One B-rep face of a CAD part: STEP entity #277.
In plain terms, the cylindrical face has radius 42.5 mm (diameter 85 mm), a partial arc.
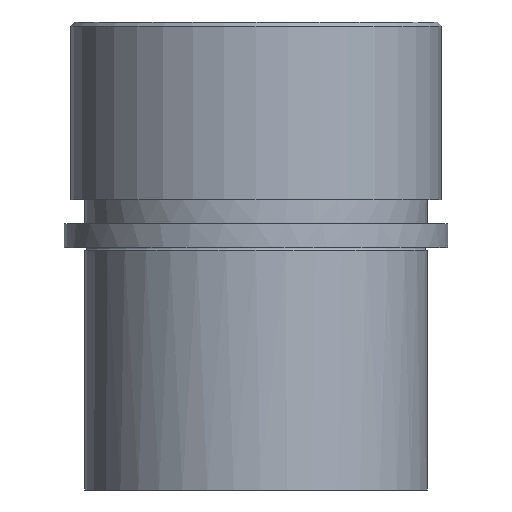
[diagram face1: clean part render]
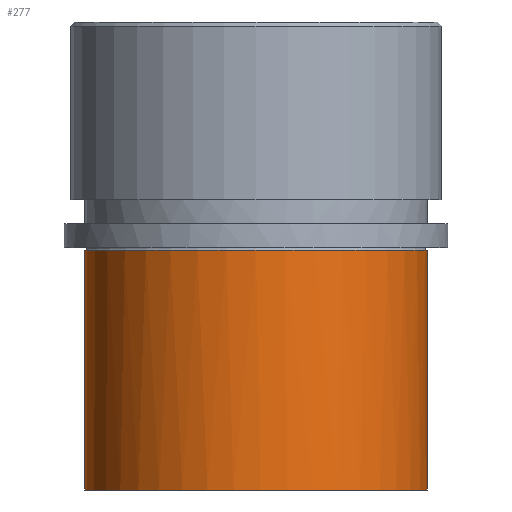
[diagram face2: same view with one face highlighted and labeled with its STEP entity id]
Its self-contained STEP definition (entity closure, numbers rounded to 3 decimals):
#109=CARTESIAN_POINT('Control Point',(-42.5,0.,-60.)) ;
#110=CARTESIAN_POINT('Control Point',(-42.5,-4.152,-60.)) ;
#111=CARTESIAN_POINT('Control Point',(-41.993,-8.304,-60.)) ;
#112=CARTESIAN_POINT('Control Point',(-40.979,-12.373,-60.)) ;
#113=CARTESIAN_POINT('Control Point',(-37.978,-20.182,-60.)) ;
#114=CARTESIAN_POINT('Control Point',(-33.186,-27.038,-60.)) ;
#115=CARTESIAN_POINT('Control Point',(-30.381,-30.156,-60.)) ;
#116=CARTESIAN_POINT('Control Point',(-24.066,-35.643,-60.)) ;
#117=CARTESIAN_POINT('Control Point',(-16.617,-39.449,-60.)) ;
#118=CARTESIAN_POINT('Control Point',(-12.677,-40.886,-60.)) ;
#119=CARTESIAN_POINT('Control Point',(-4.526,-42.768,-60.)) ;
#120=CARTESIAN_POINT('Control Point',(3.838,-42.634,-60.)) ;
#121=CARTESIAN_POINT('Control Point',(7.992,-42.053,-60.)) ;
#122=CARTESIAN_POINT('Control Point',(16.073,-39.891,-60.)) ;
#123=CARTESIAN_POINT('Control Point',(23.396,-35.847,-60.)) ;
#124=CARTESIAN_POINT('Control Point',(26.791,-33.385,-60.)) ;
#125=CARTESIAN_POINT('Control Point',(32.912,-27.683,-60.)) ;
#126=CARTESIAN_POINT('Control Point',(37.481,-20.676,-60.)) ;
#127=CARTESIAN_POINT('Control Point',(39.325,-16.909,-60.)) ;
#128=CARTESIAN_POINT('Control Point',(41.279,-11.248,-60.)) ;
#129=CARTESIAN_POINT('Control Point',(42.217,-5.37,-60.)) ;
#130=CARTESIAN_POINT('Control Point',(42.406,-3.585,-60.)) ;
#131=CARTESIAN_POINT('Control Point',(42.5,-1.792,-60.)) ;
#132=CARTESIAN_POINT('Control Point',(42.5,0.,-60.)) ;
#133=CARTESIAN_POINT('Vertex',(-42.5,0.,-60.)) ;
#135=CARTESIAN_POINT('Vertex',(42.5,0.,-60.)) ;
#247=CARTESIAN_POINT('Axis2P3D Location',(0.,0.,56.)) ;
#252=CARTESIAN_POINT('Line Origine',(42.5,0.,56.)) ;
#256=CARTESIAN_POINT('Vertex',(42.5,0.,-0.6)) ;
#259=CARTESIAN_POINT('Axis2P3D Location',(0.,0.,-0.6)) ;
#263=CARTESIAN_POINT('Vertex',(-42.5,0.,-0.6)) ;
#266=CARTESIAN_POINT('Line Origine',(-42.5,0.,56.)) ;
#248=DIRECTION('Axis2P3D Direction',(0.,0.,-1.)) ;
#249=DIRECTION('Axis2P3D XDirection',(1.,0.,0.)) ;
#253=DIRECTION('Vector Direction',(0.,0.,-1.)) ;
#260=DIRECTION('Axis2P3D Direction',(0.,0.,-1.)) ;
#267=DIRECTION('Vector Direction',(0.,0.,-1.)) ;
#250=AXIS2_PLACEMENT_3D('Cylinder Axis2P3D',#247,#248,#249) ;
#261=AXIS2_PLACEMENT_3D('Circle Axis2P3D',#259,#260,$) ;
#272=ORIENTED_EDGE('',*,*,#258,.T.) ;
#273=ORIENTED_EDGE('',*,*,#265,.F.) ;
#274=ORIENTED_EDGE('',*,*,#270,.T.) ;
#275=ORIENTED_EDGE('',*,*,#137,.T.) ;
#254=VECTOR('Line Direction',#253,1.) ;
#268=VECTOR('Line Direction',#267,1.) ;
#277=ADVANCED_FACE('735-63',(#276),#251,.T.) ;
#108=B_SPLINE_CURVE_WITH_KNOTS('',5,(#109,#110,#111,#112,#113,#114,#115,#116,#117,#118,#119,#120,#121,#122,#123,#124,#125,#126,#127,#128,#129,#130,#131,#132),.UNSPECIFIED.,.F.,.U.,(6,3,3,3,3,3,3,6),(0.,29.358,58.716,88.073,117.431,146.789,176.147,188.821),.UNSPECIFIED.) ;
#262=CIRCLE('generated circle',#261,42.5) ;
#251=CYLINDRICAL_SURFACE('generated cylinder',#250,42.5) ;
#137=EDGE_CURVE('',#134,#136,#108,.T.) ;
#258=EDGE_CURVE('',#136,#257,#255,.F.) ;
#265=EDGE_CURVE('',#264,#257,#262,.F.) ;
#270=EDGE_CURVE('',#264,#134,#269,.T.) ;
#271=EDGE_LOOP('',(#272,#273,#274,#275)) ;
#276=FACE_OUTER_BOUND('',#271,.T.) ;
#255=LINE('Line',#252,#254) ;
#269=LINE('Line',#266,#268) ;
#134=VERTEX_POINT('',#133) ;
#136=VERTEX_POINT('',#135) ;
#257=VERTEX_POINT('',#256) ;
#264=VERTEX_POINT('',#263) ;
